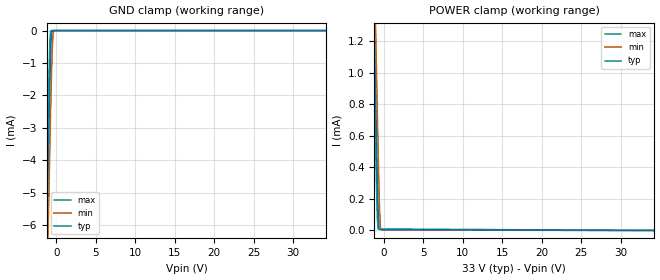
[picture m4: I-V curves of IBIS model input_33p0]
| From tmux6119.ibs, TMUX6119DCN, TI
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|   input_33p0 Model
[Model]   input_33p0
Model_type   Input
Vinl = 2
Vinh = 0.8
|   typ   min   max
C_comp   0.334pF   0.331pf   0.337pF
| Where Nom  PVT is Nominal Process, 33V, 25C
|   Fast PVT is Strong Process,  36V, -40C
|   Slow PVT is Weak Process,   30V, 125C
[Voltage Range]   33   30   36
|Junction Temperature
[Temperature Range]   27   125   -40
[Power Clamp Reference]   33   30   36
[GND Clamp Reference]   0   0   0
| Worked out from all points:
|   GND clamp passes 1 mA (typ) near -0.77 V on its own axis
|   POWER clamp passes 1 mA (typ) near -1.11 V on its own axis
[GND Clamp]
|   Voltage   I(typ)   I(min)   I(max)
-33V      -463.1mA   -480.7mA   -446.3mA
-1.32V    -7.565mA   -9.666mA   -6.184mA
-1.221V   -6.308mA   -8.414mA   -4.92mA
-1.122V   -5.066mA   -7.173mA   -3.675mA
-1.023V   -3.844mA   -5.945mA   -2.463mA
-825mV    -1.545mA   -3.561mA   -379.8uA
-726mV    -602.3uA   -2.435mA   -17.65uA
-627mV    -87.02uA   -1.405mA   -214.9nA
-528mV    -3.22uA    -579.6uA   -3.588nA
-429mV    -27.09nA   -122.6uA   -1.794nA
-231mV    0A         -620.3nA   0A
66V       0A         0A         0A
[POWER Clamp]
|   Voltage   I(typ)   I(min)   I(max)
-33V      213.6mA    271mA      156.6mA
-1.419V   1.797mA    2.242mA    1.516mA
-1.32V    1.539mA    1.984mA    1.257mA
-1.221V   1.283mA    1.728mA    1.001mA
-1.023V   780.4uA    1.223mA    501.1uA
-825mV    308.9uA    733uA      74.64uA
-726mV    113.5uA    500.1uA    10.93uA
-627mV    15.56uA    284.7uA    9.264uA
-528mV    5.778uA    108.7uA    9.227uA
-429mV    5.498uA    19.19uA    9.203uA
-231mV    5.462uA    3.047uA    9.156uA
66V       0A         0A         0A
